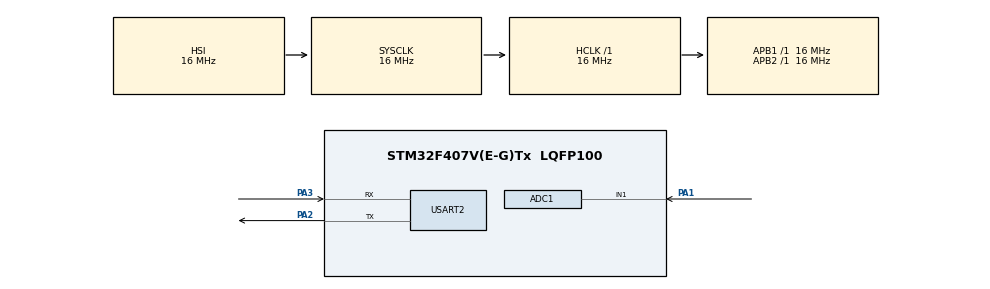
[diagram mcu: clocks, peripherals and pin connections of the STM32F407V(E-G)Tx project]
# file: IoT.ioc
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ADC1.Channel-0\#ChannelRegularConversion=ADC_CHANNEL_1
ADC1.NbrOfConversionFlag=1
ADC1.Rank-0\#ChannelRegularConversion=1
ADC1.SamplingTime-0\#ChannelRegularConversion=ADC_SAMPLETIME_3CYCLES
ADC1.master=1
Dma.Request0=USART2_RX
Dma.USART2_RX.0.Direction=DMA_PERIPH_TO_MEMORY
Dma.USART2_RX.0.FIFOMode=DMA_FIFOMODE_DISABLE
Dma.USART2_RX.0.Instance=DMA1_Stream5
Dma.USART2_RX.0.MemDataAlignment=DMA_MDATAALIGN_BYTE
Dma.USART2_RX.0.MemInc=DMA_MINC_ENABLE
Dma.USART2_RX.0.Mode=DMA_NORMAL
Dma.USART2_RX.0.PeriphDataAlignment=DMA_PDATAALIGN_BYTE
Dma.USART2_RX.0.PeriphInc=DMA_PINC_DISABLE
Dma.USART2_RX.0.Priority=DMA_PRIORITY_LOW
Mcu.Family=STM32F4
Mcu.Name=STM32F407V(E-G)Tx
Mcu.Package=LQFP100
NVIC.DMA1_Stream5_IRQn=true\:0\:0\:false\:false\:true\:false\:true\:true
NVIC.PriorityGroup=NVIC_PRIORITYGROUP_4
NVIC.USART2_IRQn=true\:0\:0\:false\:false\:true\:true\:true\:true
PA1.Signal=ADCx_IN1
PA2.GPIO_PuPd=GPIO_PULLUP
PA2.Mode=Asynchronous
PA2.Signal=USART2_TX
PA3.GPIO_PuPd=GPIO_PULLUP
PA3.Mode=Asynchronous
PA3.Signal=USART2_RX
ProjectManager.HeapSize=0x200
ProjectManager.StackSize=0x400
ProjectManager.TargetToolchain=EWARM V8.32
RCC.AHBFreq_Value=16000000
RCC.APB1Freq_Value=16000000
RCC.APB2Freq_Value=16000000
RCC.CortexFreq_Value=16000000
RCC.HSE_VALUE=25000000
RCC.HSI_VALUE=16000000
RCC.LSE_VALUE=32768
RCC.SYSCLKFreq_VALUE=16000000
RCC.VCOOutputFreq_Value=192000000
SH.ADCx_IN1.0=ADC1_IN1,IN1
USART2.VirtualMode=VM_ASYNC
board=custom

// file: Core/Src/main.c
/* USER CODE BEGIN Header */
/**
******************************************************************************
* @file           : main.c
* @brief          : Main program body
******************************************************************************
* @attention
*
* <h2><center>&copy; Copyright (c) 2021 STMicroelectronics.
* All rights reserved.</center></h2>
*
* This software component is licensed by ST under BSD 3-Clause license,
* the "License"; You may not use this file except in compliance with the
* License. You may obtain a copy of the License at:
*                        opensource.org/licenses/BSD-3-Clause
*
******************************************************************************
*/
/* USER CODE END Header */
#include "main.h"

/* USER CODE BEGIN Includes */
#include "string.h"
#include "stdio.h"
/* USER CODE END Includes */

ADC_HandleTypeDef hadc1;

UART_HandleTypeDef huart2;
DMA_HandleTypeDef hdma_usart2_rx;

/* USER CODE BEGIN PV */

uint8_t __CIPSEND[20]  =  "";

uint8_t RxDataBuffer[40];
uint16_t RxTimeOut = 2;
uint8_t i = 0;
uint32_t previousCounter = 256;
uint8_t UART_DMA_DataIsReady = 0;
char DMA_Buffer [256];
char CPU_Buffer [256];
char response [50];
char result [50];
char * charater;
char __OK[] = "OK";
char BUFFER_TO_SEND[100];

uint8_t ADCVal=0;
/* USER CODE END PV */

void SystemClock_Config(void);
static void MX_GPIO_Init(void);
static void MX_DMA_Init(void);
static void MX_ADC1_Init(void);
static void MX_USART2_UART_Init(void);
/* USER CODE BEGIN PFP */
void ESP8266_Init (void);
void ESP8266_SendServer (void);
/* USER CODE END PFP */

int main(void)
{

  /* MCU Configuration--------------------------------------------------------*/

  /* Reset of all peripherals, Initializes the Flash interface and the Systick. */
  HAL_Init();

  /* Configure the system clock */
  SystemClock_Config();

  /* Initialize all configured peripherals */
  MX_GPIO_Init();
  MX_DMA_Init();
  MX_ADC1_Init();
  MX_USART2_UART_Init();
  /* USER CODE BEGIN 2 */
  ESP8266_Init();

  /* USER CODE END 2 */

  /* Infinite loop */
  /* USER CODE BEGIN WHILE */
  while (1)
  {
    ESP8266_SendServer();

    /* USER CODE END WHILE */

  }
}

void SystemClock_Config(void)
{
  RCC_OscInitTypeDef RCC_OscInitStruct = {0};
  RCC_ClkInitTypeDef RCC_ClkInitStruct = {0};

  /** Configure the main internal regulator output voltage
  */
  __HAL_RCC_PWR_CLK_ENABLE();
  __HAL_PWR_VOLTAGESCALING_CONFIG(PWR_REGULATOR_VOLTAGE_SCALE1);

  /** Initializes the RCC Oscillators according to the specified parameters
  * in the RCC_OscInitTypeDef structure.
  */
  RCC_OscInitStruct.OscillatorType = RCC_OSCILLATORTYPE_HSI;
  RCC_OscInitStruct.HSIState = RCC_HSI_ON;
  RCC_OscInitStruct.HSICalibrationValue = RCC_HSICALIBRATION_DEFAULT;
  RCC_OscInitStruct.PLL.PLLState = RCC_PLL_NONE;
  if (HAL_RCC_OscConfig(&RCC_OscInitStruct) != HAL_OK)
  {
    Error_Handler();
  }

  /** Initializes the CPU, AHB and APB buses clocks
  */
  RCC_ClkInitStruct.ClockType = RCC_CLOCKTYPE_HCLK|RCC_CLOCKTYPE_SYSCLK
    |RCC_CLOCKTYPE_PCLK1|RCC_CLOCKTYPE_PCLK2;
  RCC_ClkInitStruct.SYSCLKSource = RCC_SYSCLKSOURCE_HSI;
  RCC_ClkInitStruct.AHBCLKDivider = RCC_SYSCLK_DIV1;
  RCC_ClkInitStruct.APB1CLKDivider = RCC_HCLK_DIV1;
  RCC_ClkInitStruct.APB2CLKDivider = RCC_HCLK_DIV1;

  if (HAL_RCC_ClockConfig(&RCC_ClkInitStruct, FLASH_LATENCY_0) != HAL_OK)
  {
    Error_Handler();
  }
}

static void MX_ADC1_Init(void)
{

  ADC_ChannelConfTypeDef sConfig = {0};

  /** Configure the global features of the ADC (Clock, Resolution, Data Alignment and number of conversion)
  */
  hadc1.Instance = ADC1;
  hadc1.Init.ClockPrescaler = ADC_CLOCK_SYNC_PCLK_DIV2;
  hadc1.Init.Resolution = ADC_RESOLUTION_12B;
  hadc1.Init.ScanConvMode = DISABLE;
  hadc1.Init.ContinuousConvMode = DISABLE;
  hadc1.Init.DiscontinuousConvMode = DISABLE;
  hadc1.Init.ExternalTrigConvEdge = ADC_EXTERNALTRIGCONVEDGE_NONE;
  hadc1.Init.ExternalTrigConv = ADC_SOFTWARE_START;
  hadc1.Init.DataAlign = ADC_DATAALIGN_RIGHT;
  hadc1.Init.NbrOfConversion = 1;
  hadc1.Init.DMAContinuousRequests = DISABLE;
  hadc1.Init.EOCSelection = ADC_EOC_SINGLE_CONV;
  if (HAL_ADC_Init(&hadc1) != HAL_OK)
  {
    Error_Handler();
  }

  /** Configure for the selected ADC regular channel its corresponding rank in the sequencer and its sample time.
  */
  sConfig.Channel = ADC_CHANNEL_1;
  sConfig.Rank = 1;
  sConfig.SamplingTime = ADC_SAMPLETIME_3CYCLES;
  if (HAL_ADC_ConfigChannel(&hadc1, &sConfig) != HAL_OK)
  {
    Error_Handler();
  }

}

static void MX_USART2_UART_Init(void)
{

  huart2.Instance = USART2;
  huart2.Init.BaudRate = 115200;
  huart2.Init.WordLength = UART_WORDLENGTH_8B;
  huart2.Init.StopBits = UART_STOPBITS_1;
  huart2.Init.Parity = UART_PARITY_NONE;
  huart2.Init.Mode = UART_MODE_TX_RX;
  huart2.Init.HwFlowCtl = UART_HWCONTROL_NONE;
  huart2.Init.OverSampling = UART_OVERSAMPLING_16;
  if (HAL_UART_Init(&huart2) != HAL_OK)
  {
    Error_Handler();
  }

}

static void MX_DMA_Init(void)
{

  /* DMA controller clock enable */
  __HAL_RCC_DMA1_CLK_ENABLE();

  /* DMA interrupt init */
  /* DMA1_Stream5_IRQn interrupt configuration */
  HAL_NVIC_SetPriority(DMA1_Stream5_IRQn, 0, 0);
  HAL_NVIC_EnableIRQ(DMA1_Stream5_IRQn);

}

static void MX_GPIO_Init(void)
{
  GPIO_InitTypeDef GPIO_InitStruct = {0};

  /* GPIO Ports Clock Enable */
  __HAL_RCC_GPIOA_CLK_ENABLE();
  /* GPIO Ports Clock Enable */
  __HAL_RCC_GPIOD_CLK_ENABLE();

  /*Configure GPIO pin Output Level */
  HAL_GPIO_WritePin(GPIOD, GPIO_PIN_15|GPIO_PIN_14|GPIO_PIN_13|GPIO_PIN_12, GPIO_PIN_RESET);

  /*Configure GPIO pin : PD12 */
  GPIO_InitStruct.Pin = GPIO_PIN_15|GPIO_PIN_14|GPIO_PIN_13|GPIO_PIN_12;
  GPIO_InitStruct.Mode = GPIO_MODE_OUTPUT_PP;
  GPIO_InitStruct.Pull = GPIO_NOPULL;
  GPIO_InitStruct.Speed = GPIO_SPEED_FREQ_LOW;
  HAL_GPIO_Init(GPIOD, &GPIO_InitStruct);
}

/* USER CODE BEGIN 4 */

/* Configure the ESP8266 - Set the WiFi */
void ESP8266_Init (void)
{
  ESP8266_SendCommand (__RST, result);
  HAL_Delay(2000);
  ESP8266_SendCommand (__AT, result);
  ESP8266_SendCommand (__CWMODE, result);
  ESP8266_Connect_To_WiFi(WIFI_NAME,WIFI_PASSWORD);
  HAL_Delay(4000);
}
void ESP8266_SendServer (void)
{
  ESP8266_SendCommand (__CIPSTART, result);

  memset (BUFFER_TO_SEND, '\0',sizeof(BUFFER_TO_SEND));
  sprintf(BUFFER_TO_SEND,"%s=%d\r\n",__SERVER_IP_WRITE,(char)ADCVal);
  sprintf((char*)__CIPSEND,"AT+CIPSEND=%d\r\n",strlen(BUFFER_TO_SEND));
  ESP8266_SendCommand (__CIPSEND, result);
  ESP8266_SendCommand((uint8_t*)&BUFFER_TO_SEND[0],result);
  ESP8266_SendCommand(__CIPCLOSE,result);

  ADCVal++;
  HAL_Delay(15000);
}
void ESP8266_Receive (void)
{
  previousCounter = 256;
  RxTimeOut = 3;
  UART_DMA_DataIsReady = 0;
  memset (DMA_Buffer, '\0',sizeof(DMA_Buffer));
  HAL_UARTEx_ReceiveToIdle_DMA(&huart2,(uint8_t*)DMA_Buffer,sizeof(DMA_Buffer));
}
void ESP8266_Connect_To_WiFi (uint8_t * wifi_name, uint8_t * password)
{
  uint8_t wifi_Command[40];
  sprintf((char*)wifi_Command,"AT+CWJAP=\"%s\",\"%s\"\r\n",wifi_name,password);
  ESP8266_SendCommand(wifi_Command, result);
}
char * ESP8266_SendCommand (uint8_t * command, char * moduleResponse)
{
  HAL_GPIO_TogglePin(GPIOD,GPIO_PIN_12);
  memset (moduleResponse, '\0',sizeof(moduleResponse));
  ESP8266_Receive();
  HAL_UART_Transmit(&huart2,command,strlen((const char*)command),0xFFFF);
  HAL_Delay(50);
  while (UART_DMA_DataIsReady == 0){}
  moduleResponse = CheckForResponse (command,moduleResponse);
  command = 0;
  return moduleResponse;
}
char * CheckForResponse (uint8_t * command, char * tmprep)
{
  charater = strstr (DMA_Buffer, __OK);

  if (charater)
  {
    memcpy (response,DMA_Buffer,sizeof(response));

    for(int i = 0; i<strlen (response);i++)
    {
      tmprep [i] = response[i +strlen((const char *)command) -1];
    }
    return tmprep;
  }
  else
    return (char*)memset (tmprep,'\0',sizeof(tmprep));
}
void HAL_UARTEx_RxEventCallback(UART_HandleTypeDef *huart, uint16_t Size)
{
  HAL_GPIO_TogglePin(GPIOD,GPIO_PIN_13);
  memset (CPU_Buffer, '\0',sizeof(CPU_Buffer));
  memcpy (CPU_Buffer,DMA_Buffer,(DMAMAXCOUNTER- DMA1_Stream5->NDTR));
  ESP8266_Receive();
  UART_DMA_DataIsReady = 1;
}
/* USER CODE END 4 */

void Error_Handler(void)
{
  /* USER CODE BEGIN Error_Handler_Debug */
  /* User can add his own implementation to report the HAL error return state */
  __disable_irq();
  while (1)
  {
    HAL_GPIO_WritePin(GPIOD,GPIO_PIN_14,GPIO_PIN_SET);
  }
  /* USER CODE END Error_Handler_Debug */
}
